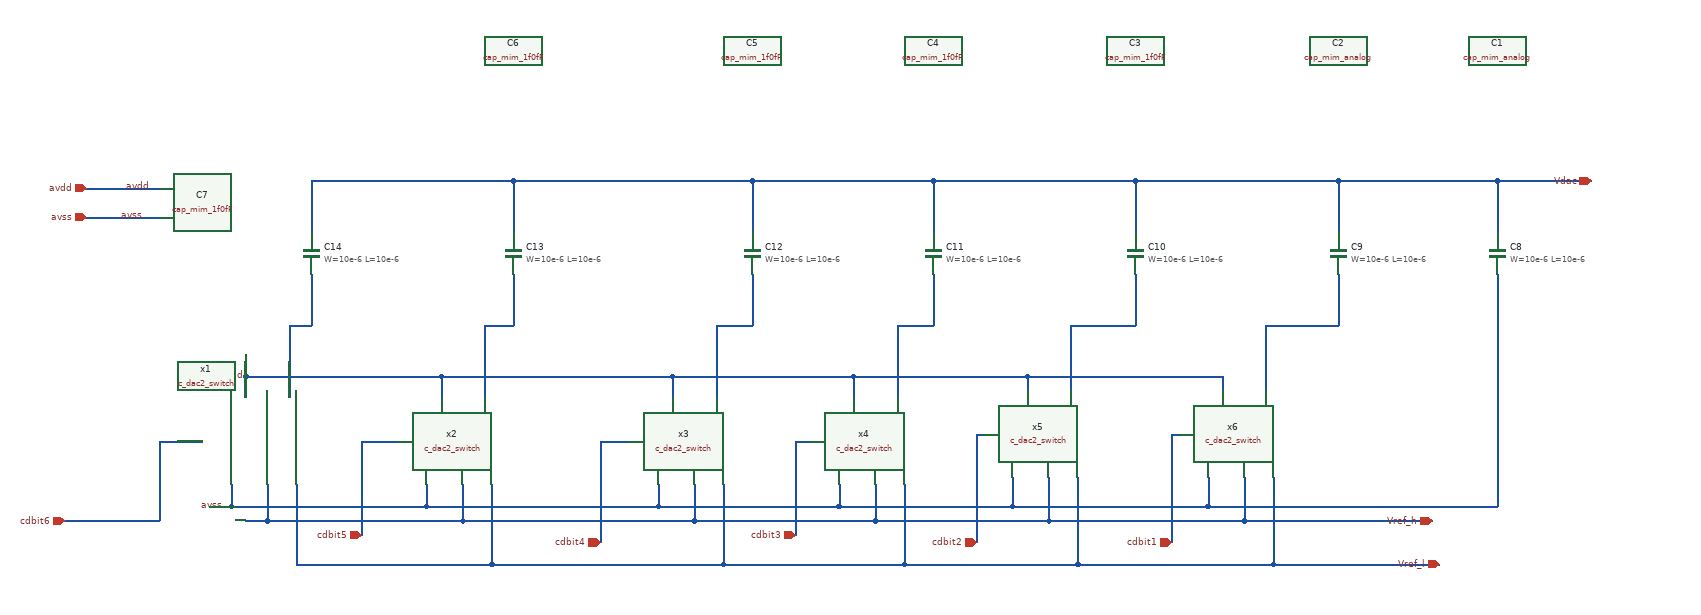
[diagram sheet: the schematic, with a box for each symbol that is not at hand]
v {xschem version=3.4.7 file_version=1.2}
G {}
K {}
V {}
S {}
E {}
P 4 1 1850 -550 {}
N 1810 -790 1810 -720 {lab=Vdac}
N 1810 -790 2030 -790 {lab=Vdac}
N 670 -790 670 -720 {lab=Vdac}
N 1000 -790 1000 -720 {lab=Vdac}
N 1250 -790 1250 -720 {lab=Vdac}
N 1530 -790 1530 -720 {lab=Vdac}
N 2030 -660 2030 -340 {lab=avss}
N 1810 -660 1810 -590 {lab=#net1}
N 1530 -660 1530 -590 {lab=#net2}
N 1250 -660 1250 -590 {lab=#net3}
N 1000 -660 1000 -590 {lab=#net4}
N 670 -660 670 -590 {lab=#net5}
N 390 -790 390 -720 {lab=Vdac}
N 2030 -790 2030 -720 {lab=Vdac}
N 390 -660 390 -590 {lab=#net6}
N 2030 -790 2160 -790 {lab=Vdac}
N 390 -790 670 -790 {lab=Vdac}
N 1530 -790 1810 -790 {lab=Vdac}
N 360 -590 390 -590 {lab=#net6}
N 360 -590 360 -490 {lab=#net6}
N 630 -590 630 -490 {lab=#net5}
N 950 -590 950 -490 {lab=#net4}
N 1200 -590 1200 -490 {lab=#net3}
N 1440 -590 1440 -500 {lab=#net2}
N 1710 -590 1710 -500 {lab=#net1}
N 80 -780 180 -780 {lab=avdd}
N 80 -740 180 -740 {lab=avss}
N 330 -370 330 -320 {lab=Vref_h}
N 300 -520 300 -490 {lab=avdd}
N 180 -430 240 -430 {lab=cdbit6}
N 570 -520 570 -490 {lab=avdd}
N 890 -520 890 -490 {lab=avdd}
N 1140 -520 1140 -490 {lab=avdd}
N 1380 -520 1380 -500 {lab=avdd}
N 1650 -520 1650 -500 {lab=avdd}
N 550 -370 550 -340 {lab=avss}
N 870 -370 870 -340 {lab=avss}
N 1630 -340 2030 -340 {lab=avss}
N 1120 -370 1120 -340 {lab=avss}
N 1360 -380 1360 -340 {lab=avss}
N 1630 -380 1630 -340 {lab=avss}
N 600 -370 600 -320 {lab=Vref_h}
N 920 -370 920 -320 {lab=Vref_h}
N 1170 -370 1170 -320 {lab=Vref_h}
N 1410 -380 1410 -320 {lab=Vref_h}
N 1680 -380 1680 -320 {lab=Vref_h}
N 870 -340 1120 -340 {lab=avss}
N 280 -370 280 -340 {lab=avss}
N 460 -430 460 -300 {lab=cdbit5}
N 790 -430 790 -290 {lab=cdbit4}
N 1060 -430 1060 -300 {lab=cdbit3}
N 1310 -440 1310 -290 {lab=cdbit2}
N 1580 -440 1580 -290 {lab=cdbit1}
N 180 -430 180 -320 {lab=cdbit6}
N 670 -790 1000 -790 {lab=Vdac}
N 1000 -790 1250 -790 {lab=Vdac}
N 1250 -790 1530 -790 {lab=Vdac}
N 300 -550 300 -520 {lab=avdd}
N 280 -340 550 -340 {lab=avss}
N 370 -370 370 -260 {lab=Vref_l}
N 640 -370 640 -260 {lab=Vref_l}
N 960 -370 960 -260 {lab=Vref_l}
N 1210 -370 1210 -260 {lab=Vref_l}
N 1450 -380 1450 -260 {lab=Vref_l}
N 1720 -380 1720 -260 {lab=Vref_l}
N 300 -320 330 -320 {lab=Vref_h}
N 920 -320 1170 -320 {lab=Vref_h}
N 1680 -320 1940 -320 {lab=Vref_h}
N 1720 -260 1950 -260 {lab=Vref_l}
N 960 -260 1210 -260 {lab=Vref_l}
N 330 -320 600 -320 {lab=Vref_h}
N 250 -340 280 -340 {lab=avss}
N 370 -260 640 -260 {lab=Vref_l}
N 300 -520 570 -520 {lab=avdd}
N 630 -590 670 -590 {lab=#net5}
N 570 -520 890 -520 {lab=avdd}
N 950 -590 1000 -590 {lab=#net4}
N 890 -520 1140 -520 {lab=avdd}
N 1120 -340 1360 -340 {lab=avss}
N 1170 -320 1410 -320 {lab=Vref_h}
N 1210 -260 1450 -260 {lab=Vref_l}
N 1140 -520 1380 -520 {lab=avdd}
N 1200 -590 1250 -590 {lab=#net3}
N 1440 -590 1530 -590 {lab=#net2}
N 1380 -520 1650 -520 {lab=avdd}
N 1710 -590 1810 -590 {lab=#net1}
N 1360 -340 1630 -340 {lab=avss}
N 1410 -320 1680 -320 {lab=Vref_h}
N 1450 -260 1720 -260 {lab=Vref_l}
N 460 -430 510 -430 {lab=cdbit5}
N 790 -430 830 -430 {lab=cdbit4}
N 1060 -430 1080 -430 {lab=cdbit3}
N 1310 -440 1320 -440 {lab=cdbit2}
N 1580 -440 1590 -440 {lab=cdbit1}
N 550 -340 870 -340 {lab=avss}
N 600 -320 920 -320 {lab=Vref_h}
N 640 -260 960 -260 {lab=Vref_l}
N 50 -320 180 -320 {lab=cdbit6}
C {symbols/cap_mim_1f0fF.sym} 1530 -970 0 0 {name=C3
W=20e-6
L=20e-6
model=cap_mim_2f0_m3m4_noshield
spiceprefix=X
m=2
spice_ignore=true}
C {symbols/cap_mim_1f0fF.sym} 1250 -970 0 0 {name=C4
W=20e-6
L=20e-6
model=cap_mim_2f0_m3m4_noshield
spiceprefix=X
m=4
spice_ignore=true}
C {symbols/cap_mim_1f0fF.sym} 1000 -970 0 0 {name=C5
W=20e-6
L=20e-6
model=cap_mim_2f0_m3m4_noshield
spiceprefix=X
m=8
spice_ignore=true}
C {symbols/cap_mim_1f0fF.sym} 670 -970 0 0 {name=C6
W=20e-6
L=20e-6
model=cap_mim_2f0_m3m4_noshield
spiceprefix=X
m=16
spice_ignore=true}
C {symbols/cap_mim_1f0fF.sym} 390 -970 0 0 {name=C7
W=20e-6
L=20e-6
model=cap_mim_2f0_m3m4_noshield
spiceprefix=X
m=32
spice_ignore=true}
C {iopin.sym} 1940 -320 0 0 {name=p1 lab=Vref_h}
C {iopin.sym} 2160 -790 0 0 {name=p8 lab=Vdac}
C {iopin.sym} 80 -780 2 0 {name=p9 lab=avdd}
C {iopin.sym} 80 -740 2 0 {name=p10 lab=avss}
C {lab_wire.sym} 170 -780 0 0 {name=p13 sig_type=std_logic lab=avdd}
C {lab_wire.sym} 160 -740 0 0 {name=p14 sig_type=std_logic lab=avss}
C {lab_wire.sym} 300 -520 0 0 {name=p15 sig_type=std_logic lab=avdd}
C {lab_wire.sym} 270 -340 0 0 {name=p16 sig_type=std_logic lab=avss}
C {symbols/cap_mim_analog.sym} 2030 -970 0 0 {name=C1
W=10e-6
L=10e-6
model=cap_mim_2f0_m3m4_noshield
spiceprefix=X
m=1
spice_ignore=true}
C {symbols/cap_mim_analog.sym} 1810 -970 0 0 {name=C2
W=20e-6
L=20e-6
model=cap_mim_2f0_m3m4_noshield
spiceprefix=X
m=1
spice_ignore=true}
C {iopin.sym} 50 -320 2 0 {name=p11 lab=cdbit6}
C {iopin.sym} 460 -300 2 0 {name=p12 lab=cdbit5}
C {iopin.sym} 790 -290 2 0 {name=p17 lab=cdbit4}
C {iopin.sym} 1060 -300 2 0 {name=p18 lab=cdbit3}
C {iopin.sym} 1310 -290 2 0 {name=p19 lab=cdbit2}
C {iopin.sym} 1580 -290 2 0 {name=p20 lab=cdbit1}
C {iopin.sym} 1950 -260 0 0 {name=p2 lab=Vref_l}
C {title.sym} 287.5 -10 0 0 {name=l1 author="Mia"}
C {libs/WK_Kadam/CDAC_Switch_V2/c_dac2_switch.sym} 330 -430 0 0 {name=x1}
C {libs/WK_Kadam/CDAC_Switch_V2/c_dac2_switch.sym} 600 -430 0 0 {name=x2}
C {libs/WK_Kadam/CDAC_Switch_V2/c_dac2_switch.sym} 920 -430 0 0 {name=x3}
C {libs/WK_Kadam/CDAC_Switch_V2/c_dac2_switch.sym} 1170 -430 0 0 {name=x4}
C {libs/WK_Kadam/CDAC_Switch_V2/c_dac2_switch.sym} 1410 -440 0 0 {name=x5}
C {libs/WK_Kadam/CDAC_Switch_V2/c_dac2_switch.sym} 1680 -440 0 0 {name=x6}
C {symbols/cap_mim_1f0fF.sym} 2030 -690 0 0 {name=C8
W=10e-6
L=10e-6
model=cap_mim_1f0fF
spiceprefix=X
m=1}
C {symbols/cap_mim_1f0fF.sym} 1810 -690 0 0 {name=C9
W=10e-6
L=10e-6
model=cap_mim_1f0fF
spiceprefix=X
m=1}
C {symbols/cap_mim_1f0fF.sym} 1530 -690 0 0 {name=C10
W=10e-6
L=10e-6
model=cap_mim_1f0fF
spiceprefix=X
m=2}
C {symbols/cap_mim_1f0fF.sym} 1250 -690 0 0 {name=C11
W=10e-6
L=10e-6
model=cap_mim_1f0fF
spiceprefix=X
m=4}
C {symbols/cap_mim_1f0fF.sym} 1000 -690 0 0 {name=C12
W=10e-6
L=10e-6
model=cap_mim_1f0fF
spiceprefix=X
m=8}
C {symbols/cap_mim_1f0fF.sym} 670 -690 0 0 {name=C13
W=10e-6
L=10e-6
model=cap_mim_1f0fF
spiceprefix=X
m=16}
C {symbols/cap_mim_1f0fF.sym} 390 -690 0 0 {name=C14
W=10e-6
L=10e-6
model=cap_mim_1f0fF
spiceprefix=X
m=32}
